VERSION 5.7 ;
  NOWIREEXTENSIONATPIN ON ;
  DIVIDERCHAR "/" ;
  BUSBITCHARS "[]" ;
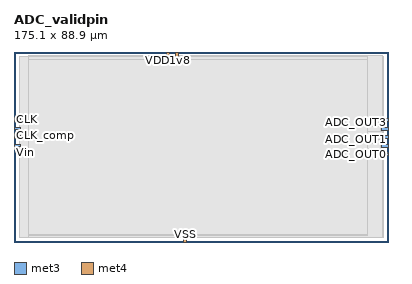
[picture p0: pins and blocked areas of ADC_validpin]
MACRO ADC_validpin
  CLASS BLOCK ;
  FOREIGN ADC_validpin ;
  ORIGIN -0.100 -0.100 ;
  SIZE 175.100 BY 88.900 ;
  PIN CLK
    ANTENNAGATEAREA 12.505000 ;
    PORT
      LAYER met3 ;
        RECT 0.100 56.600 3.200 57.900 ;
    END
  END CLK
  PIN CLK_comp
    ANTENNAGATEAREA 9.000000 ;
    PORT
      LAYER met3 ;
        RECT 0.100 52.600 3.200 53.900 ;
    END
  END CLK_comp
  PIN RST_N
    ANTENNAGATEAREA 66.000000 ;
    PORT
      LAYER met3 ;
        RECT 0.100 48.600 3.200 49.900 ;
    END
  END RST_N
  PIN Vin
    ANTENNADIFFAREA 300.000000 ;
    PORT
      LAYER met3 ;
        RECT 0.100 44.600 3.200 45.900 ;
    END
  END Vin
  PIN VALID
    ANTENNADIFFAREA 1.200000 ;
    PORT
      LAYER met3 ;
        RECT 172.100 56.400 175.200 57.700 ;
    END
  END VALID
  PIN ADC_OUT3
    ANTENNADIFFAREA 1.200000 ;
    PORT
      LAYER met3 ;
        RECT 172.100 52.400 175.200 53.700 ;
    END
  END ADC_OUT3
  PIN ADC_OUT2
    ANTENNADIFFAREA 1.200000 ;
    PORT
      LAYER met3 ;
        RECT 172.100 48.400 175.200 49.700 ;
    END
  END ADC_OUT2
  PIN ADC_OUT1
    ANTENNADIFFAREA 1.200000 ;
    PORT
      LAYER met3 ;
        RECT 172.100 44.400 175.200 45.700 ;
    END
  END ADC_OUT1
  PIN ADC_OUT0
    ANTENNADIFFAREA 1.200000 ;
    PORT
      LAYER met3 ;
        RECT 172.100 40.400 175.200 41.700 ;
    END
  END ADC_OUT0
  PIN VSS
    USE GROUND ;
    PORT
      LAYER met4 ;
        RECT 79.600 0.100 80.900 3.200 ;
    END
  END VSS
  PIN VDD1v8
    USE POWER ;
    PORT
      LAYER met4 ;
        RECT 71.600 85.900 72.900 89.000 ;
    END
  END VDD1v8
  PIN VDD_5V
    USE POWER ;
    PORT
      LAYER met4 ;
        RECT 75.600 85.900 76.900 89.000 ;
    END
  END VDD_5V
  OBS
      LAYER nwell ;
        RECT 11.450 6.000 162.300 83.150 ;
      LAYER li1 ;
        RECT 10.800 6.250 162.000 83.150 ;
      LAYER met1 ;
        RECT 2.500 2.300 172.900 86.700 ;
      LAYER met2 ;
        RECT 2.500 2.300 172.900 86.700 ;
      LAYER met3 ;
        RECT 6.820 58.100 172.700 87.200 ;
        RECT 6.820 56.000 171.700 58.100 ;
        RECT 6.820 54.100 172.700 56.000 ;
        RECT 6.820 52.000 171.700 54.100 ;
        RECT 6.820 50.100 172.700 52.000 ;
        RECT 6.820 48.000 171.700 50.100 ;
        RECT 6.820 46.100 172.700 48.000 ;
        RECT 6.820 44.000 171.700 46.100 ;
        RECT 6.820 42.100 172.700 44.000 ;
        RECT 6.820 40.000 171.700 42.100 ;
        RECT 6.820 2.300 172.700 40.000 ;
      LAYER met4 ;
        RECT 7.100 85.500 71.200 86.800 ;
        RECT 73.300 85.500 75.200 86.800 ;
        RECT 77.300 85.500 165.400 86.800 ;
        RECT 7.100 3.600 165.400 85.500 ;
        RECT 7.100 3.200 79.200 3.600 ;
        RECT 81.300 3.200 165.400 3.600 ;
  END
END ADC_validpin
END LIBRARY

